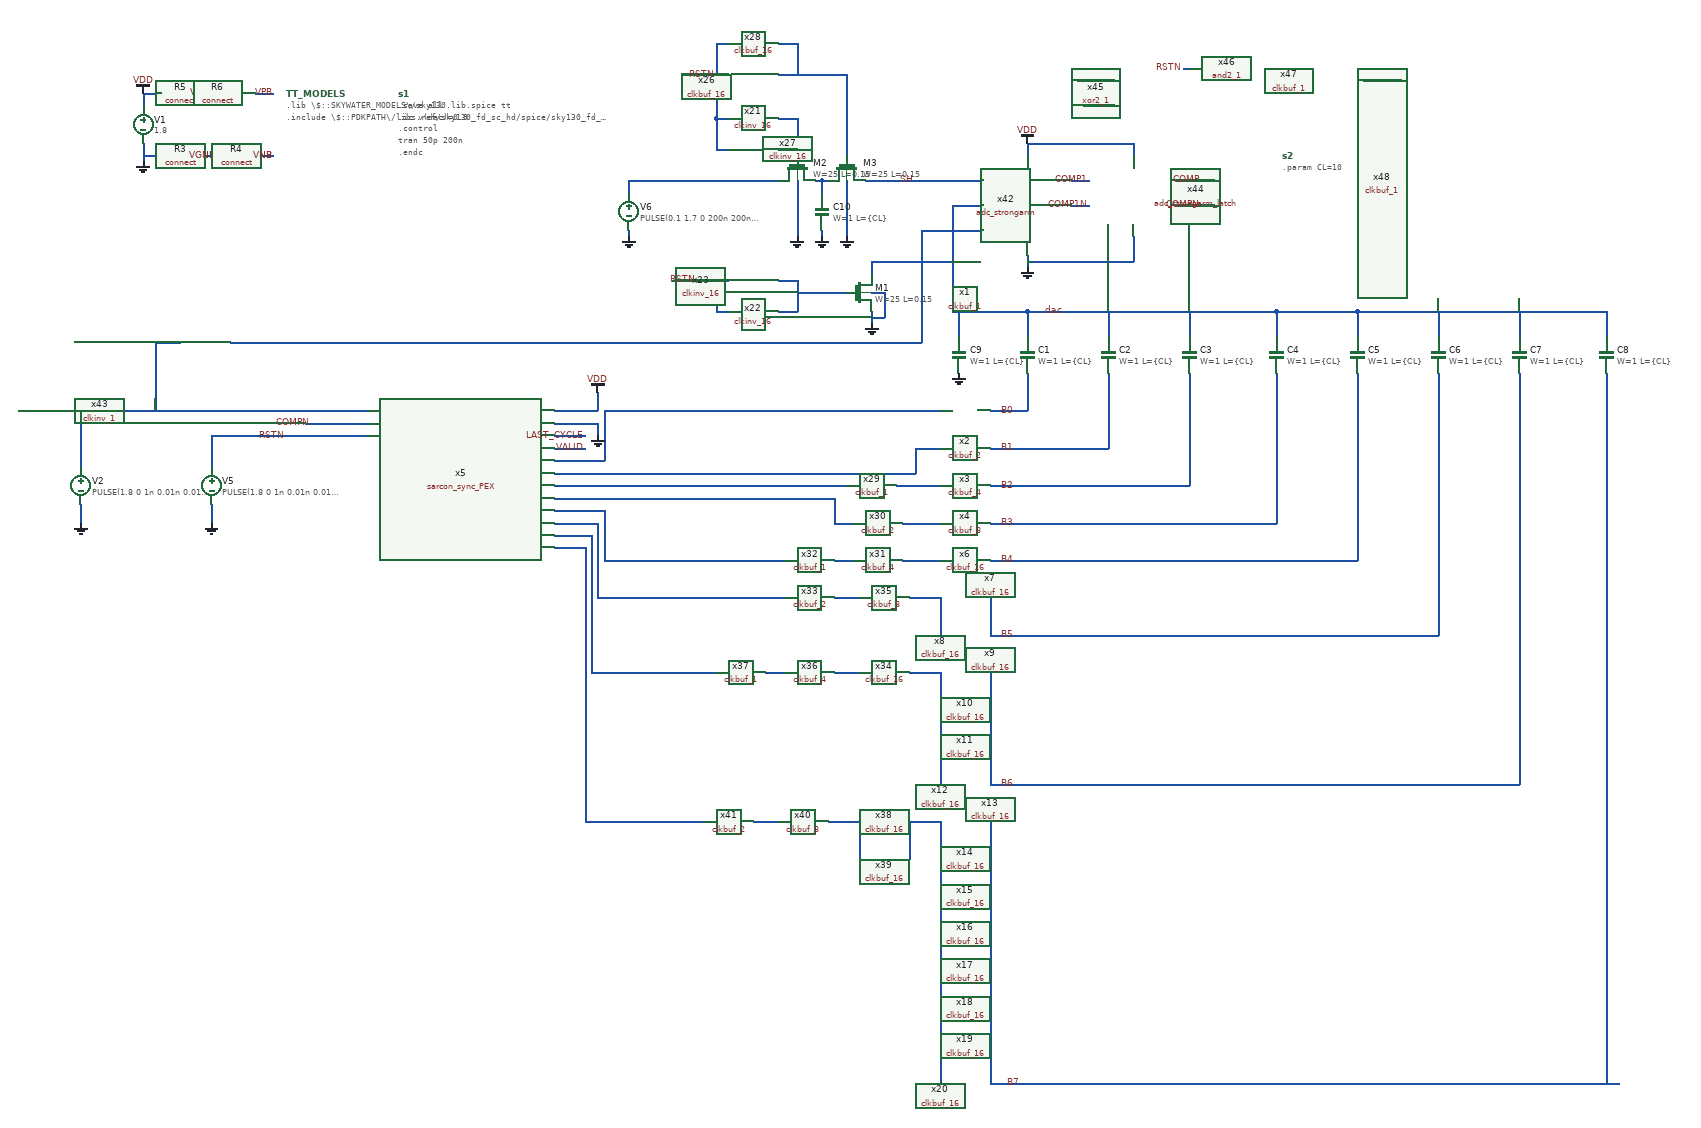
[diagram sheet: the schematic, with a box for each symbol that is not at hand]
v {xschem version=3.1.0 file_version=1.2
}
G {}
K {}
V {}
S {}
E {}
N 2640 -1240 2640 -1180 {
lab=B0}
N 2580 -1180 2640 -1180 {
lab=B0}
N 2640 -1340 2640 -1300 {
lab=dac}
N 2640 -1340 3040 -1340 {
lab=dac}
N 3040 -1340 3040 -1300 {
lab=dac}
N 2900 -1340 2900 -1300 {
lab=dac}
N 2770 -1340 2770 -1300 {
lab=dac}
N 1220 -1610 1220 -1580 {
lab=GND}
N 1220 -1590 1250 -1590 {
lab=GND}
N 1310 -1590 1340 -1590 {
lab=VGND}
N 1400 -1590 1430 -1590 {
lab=VNB}
N 1220 -1590 1250 -1590 {
lab=GND}
N 1310 -1590 1340 -1590 {
lab=VGND}
N 1400 -1590 1430 -1590 {
lab=VNB}
N 1220 -1690 1250 -1690 {
lab=VDD}
N 1310 -1690 1340 -1690 {
lab=VPWR}
N 1400 -1690 1430 -1690 {
lab=VPB}
N 1220 -1690 1220 -1670 {
lab=VDD}
N 2580 -1120 2770 -1120 {
lab=B1}
N 2770 -1240 2770 -1120 {
lab=B1}
N 2580 -1060 2900 -1060 {
lab=B2}
N 2900 -1240 2900 -1060 {
lab=B2}
N 2580 -1000 3030 -1000 {
lab=B3}
N 3030 -1000 3040 -1000 {
lab=B3}
N 3040 -1240 3040 -1000 {
lab=B3}
N 1330 -1030 1330 -1000 {
lab=GND}
N 1330 -1140 1330 -1090 {
lab=RSTN}
N 1020 -1180 1290 -1180 {
lab=#net1}
N 1880 -1180 1950 -1180 {
lab=VDD}
N 1950 -1210 1950 -1180 {
lab=VDD}
N 1880 -1160 1950 -1160 {
lab=GND}
N 1950 -1160 1950 -1140 {
lab=GND}
N 1290 -1180 1580 -1180 {
lab=#net1}
N 1540 -1140 1580 -1140 {
lab=RSTN}
N 1330 -1140 1540 -1140 {
lab=RSTN}
N 2580 -940 2640 -940 {
lab=B4}
N 3170 -1340 3570 -1340 {
lab=dac}
N 3570 -1340 3570 -1300 {
lab=dac}
N 3430 -1340 3430 -1300 {
lab=dac}
N 3300 -1340 3300 -1300 {
lab=dac}
N 3170 -1340 3170 -1300 {
lab=dac}
N 3040 -1340 3170 -1340 {
lab=dac}
N 2580 -880 2580 -820 {
lab=B5}
N 2500 -880 2500 -820 {
lab=#net2}
N 2640 -940 3170 -940 {
lab=B4}
N 3170 -1240 3170 -940 {
lab=B4}
N 2580 -820 3300 -820 {
lab=B5}
N 3300 -1240 3300 -820 {
lab=B5}
N 2500 -760 2500 -580 {
lab=#net3}
N 2580 -760 2580 -580 {
lab=B6}
N 2500 -520 2500 -340 {
lab=#net4}
N 2580 -520 2580 -340 {
lab=B7}
N 2500 -280 2500 -100 {
lab=#net4}
N 2580 -280 2580 -100 {
lab=B7}
N 2580 -340 2580 -280 {
lab=B7}
N 2500 -340 2500 -280 {
lab=#net4}
N 2580 -100 3590 -100 {
lab=B7}
N 3570 -1240 3570 -100 {
lab=B7}
N 3430 -1240 3430 -590 {
lab=B6}
N 3430 -590 3430 -580 {
lab=B6}
N 2580 -580 3430 -580 {
lab=B6}
N 1960 -1180 2010 -1180 {
lab=#net5}
N 1960 -1180 1960 -1100 {
lab=#net5}
N 1880 -1100 1960 -1100 {
lab=#net5}
N 1880 -1080 1970 -1080 {
lab=#net6}
N 2460 -1120 2460 -1080 {
lab=#net6}
N 2460 -1120 2500 -1120 {
lab=#net6}
N 1880 -1060 2010 -1060 {
lab=#net7}
N 1880 -1040 1970 -1040 {
lab=#net8}
N 2460 -1000 2500 -1000 {
lab=#net9}
N 1880 -1020 1960 -1020 {
lab=#net10}
N 1960 -1020 1960 -940 {
lab=#net10}
N 1960 -940 2010 -940 {
lab=#net10}
N 1880 -1000 1950 -1000 {
lab=#net11}
N 1950 -1000 1950 -880 {
lab=#net11}
N 1950 -880 2010 -880 {
lab=#net11}
N 1880 -980 1940 -980 {
lab=#net12}
N 1940 -980 1940 -760 {
lab=#net12}
N 1940 -760 2010 -760 {
lab=#net12}
N 1880 -960 1930 -960 {
lab=#net13}
N 1930 -960 1930 -520 {
lab=#net13}
N 1930 -520 2000 -520 {
lab=#net13}
N 2490 -520 2500 -520 {
lab=#net4}
N 2010 -1180 2500 -1180 {
lab=#net5}
N 1970 -1080 2460 -1080 {
lab=#net6}
N 2430 -1060 2500 -1060 {
lab=#net14}
N 2010 -1060 2350 -1060 {
lab=#net7}
N 2440 -1000 2460 -1000 {
lab=#net9}
N 2330 -1000 2360 -1000 {
lab=#net8}
N 2330 -1040 2330 -1000 {
lab=#net8}
N 1970 -1040 2330 -1040 {
lab=#net8}
N 2440 -940 2500 -940 {
lab=#net15}
N 2330 -940 2360 -940 {
lab=#net16}
N 2010 -940 2250 -940 {
lab=#net10}
N 2450 -880 2500 -880 {
lab=#net2}
N 2330 -880 2370 -880 {
lab=#net17}
N 2010 -880 2250 -880 {
lab=#net11}
N 2450 -760 2500 -760 {
lab=#net3}
N 2220 -760 2250 -760 {
lab=#net18}
N 2330 -760 2370 -760 {
lab=#net19}
N 2010 -760 2140 -760 {
lab=#net12}
N 2450 -520 2450 -460 {
lab=#net4}
N 2370 -520 2370 -460 {
lab=#net20}
N 2320 -520 2370 -520 {
lab=#net20}
N 2200 -520 2240 -520 {
lab=#net21}
N 2450 -520 2490 -520 {
lab=#net4}
N 2000 -520 2120 -520 {
lab=#net13}
N 2520 -1510 2570 -1510 {
lab=dac}
N 2520 -1510 2520 -1340 {
lab=dac}
N 2520 -1340 2640 -1340 {
lab=dac}
N 2470 -1470 2570 -1470 {
lab=#net22}
N 2470 -1470 2470 -1290 {
lab=#net22}
N 1360 -1290 2470 -1290 {
lab=#net22}
N 1240 -1290 1280 -1290 {
lab=#net1}
N 1240 -1290 1240 -1180 {
lab=#net1}
N 2640 -1430 2640 -1410 {
lab=GND}
N 2640 -1610 2640 -1590 {
lab=VDD}
N 2710 -1550 2740 -1550 {
lab=COMP1}
N 2710 -1510 2740 -1510 {
lab=COMP1N}
N 2640 -1420 2810 -1420 {
lab=GND}
N 2810 -1460 2810 -1420 {
lab=GND}
N 2640 -1610 2810 -1610 {
lab=VDD}
N 2810 -1610 2810 -1590 {
lab=VDD}
N 2880 -1550 2940 -1550 {
lab=COMP}
N 2880 -1510 2940 -1510 {
lab=COMPN}
N 1480 -1160 1580 -1160 {
lab=COMPN}
N 2000 -1470 2000 -1460 {
lab=GND}
N 2730 -1710 2780 -1710 {
lab=#net23}
N 2720 -1710 2730 -1710 {
lab=#net23}
N 2740 -1670 2780 -1670 {
lab=#net24}
N 2730 -1670 2740 -1670 {
lab=#net24}
N 3180 -1710 3240 -1710 {
lab=ASCLK}
N 2890 -1730 2900 -1730 {
lab=RSTN}
N 1880 -1120 1930 -1120 {
lab=VALID}
N 1880 -1140 1930 -1140 {
lab=LAST_CYCLE}
N 2530 -1340 2530 -1300 {
lab=dac}
N 2390 -1420 2390 -1400 {
lab=dac}
N 2390 -1420 2520 -1420 {
lab=dac}
N 2390 -1340 2390 -1320 {
lab=GND}
N 2390 -1330 2410 -1330 {
lab=GND}
N 2410 -1370 2410 -1330 {
lab=GND}
N 2390 -1370 2410 -1370 {
lab=GND}
N 2310 -1470 2310 -1460 {
lab=GND}
N 2000 -1550 2000 -1530 {
lab=#net25}
N 2300 -1550 2310 -1550 {
lab=#net26}
N 2310 -1550 2310 -1530 {
lab=#net26}
N 2310 -1550 2320 -1550 {
lab=#net26}
N 2350 -1550 2350 -1460 {
lab=GND}
N 2270 -1550 2270 -1460 {
lab=GND}
N 2380 -1550 2570 -1550 {
lab=SH}
N 2240 -1650 2270 -1650 {
lab=#net27}
N 2270 -1650 2270 -1590 {
lab=#net27}
N 2240 -1720 2350 -1720 {
lab=#net28}
N 2350 -1720 2350 -1590 {
lab=#net28}
N 2090 -1720 2160 -1720 {
lab=RSTN}
N 2140 -1650 2160 -1650 {
lab=RSTN}
N 2140 -1720 2140 -1650 {
lab=RSTN}
N 2240 -1600 2270 -1600 {
lab=#net27}
N 2140 -1650 2140 -1600 {
lab=RSTN}
N 2140 -1600 2160 -1600 {
lab=RSTN}
N 2240 -1770 2270 -1770 {
lab=#net28}
N 2270 -1770 2270 -1720 {
lab=#net28}
N 2140 -1770 2160 -1770 {
lab=RSTN}
N 2140 -1770 2140 -1720 {
lab=RSTN}
N 2240 -1390 2270 -1390 {
lab=#net29}
N 2270 -1390 2270 -1340 {
lab=#net29}
N 2240 -1340 2270 -1340 {
lab=#net29}
N 2270 -1370 2350 -1370 {
lab=#net29}
N 2140 -1390 2160 -1390 {
lab=RSTN}
N 2140 -1390 2140 -1340 {
lab=RSTN}
N 2140 -1340 2160 -1340 {
lab=RSTN}
N 2070 -1390 2140 -1390 {
lab=RSTN}
N 2000 -1550 2240 -1550 {
lab=#net25}
N 1120 -1180 1120 -1090 {
lab=#net1}
N 1120 -1030 1120 -1000 {
lab=GND}
C {sky130_stdcells/clkbuf_1.sym} 2540 -1180 0 0 {name=x1 VGND=VGND VNB=VNB VPB=VPB VPWR=VPWR prefix=sky130_fd_sc_hd__ }
C {sky130_fd_pr/cap_mim_m3_1.sym} 2640 -1270 0 0 {name=C1 model=cap_mim_m3_1 W=1 L=\{CL\} MF=1 spiceprefix=X}
C {devices/lab_wire.sym} 2700 -1340 0 0 {name=p1 sig_type=std_logic lab=dac}
C {devices/vsource.sym} 1220 -1640 0 0 {name=V1 value=1.8}
C {devices/gnd.sym} 1220 -1580 0 0 {name=l1 lab=GND}
C {devices/lab_wire.sym} 1340 -1590 0 0 {name=p2 sig_type=std_logic lab=VGND}
C {devices/lab_wire.sym} 1430 -1590 0 0 {name=p3 sig_type=std_logic lab=VNB}
C {devices/connect.sym} 1280 -1590 1 0 {name=R3 m=1}
C {devices/lab_wire.sym} 1340 -1590 0 0 {name=p4 sig_type=std_logic lab=VGND}
C {devices/connect.sym} 1370 -1590 1 0 {name=R4 m=1}
C {devices/lab_wire.sym} 1430 -1590 0 0 {name=p5 sig_type=std_logic lab=VNB}
C {devices/connect.sym} 1280 -1690 1 0 {name=R5 m=1}
C {devices/lab_wire.sym} 1340 -1690 0 0 {name=p6 sig_type=std_logic lab=VPWR}
C {devices/connect.sym} 1370 -1690 1 0 {name=R6 m=1}
C {devices/lab_wire.sym} 1430 -1690 0 0 {name=p7 sig_type=std_logic lab=VPB}
C {devices/vsource.sym} 1330 -1060 0 0 {name=V5 value="PULSE(1.8 0 1n 0.01n 0.01n 4n 20n)"}
C {devices/gnd.sym} 1330 -1000 0 0 {name=l2 lab=GND}
C {devices/code.sym} 1450 -1690 0 0 {name=TT_MODELS only_toplevel=false
format="tcleval(@value )" value=".lib \\\\$::SKYWATER_MODELS\\\\/sky130.lib.spice tt
.include \\\\$::PDKPATH\\\\/libs.ref/sky130_fd_sc_hd/spice/sky130_fd_sc_hd.spice
"}
C {devices/code_shown.sym} 1630 -1690 0 0 {name=s1
only_toplevel=false
value="
.save all
.ic v(dac)=0.9
.control
tran 50p 200n
.endc
"}
C {devices/lab_wire.sym} 2620 -1180 0 0 {name=p8 sig_type=std_logic lab=B0}
C {devices/lab_wire.sym} 2620 -1120 0 0 {name=p9 sig_type=std_logic lab=B1}
C {devices/lab_wire.sym} 2620 -1060 0 0 {name=p10 sig_type=std_logic lab=B2}
C {devices/lab_wire.sym} 2620 -1000 0 0 {name=p11 sig_type=std_logic lab=B3}
C {sky130_stdcells/clkbuf_2.sym} 2540 -1120 0 0 {name=x2 VGND=VGND VNB=VNB VPB=VPB VPWR=VPWR prefix=sky130_fd_sc_hd__ }
C {sky130_stdcells/clkbuf_4.sym} 2540 -1060 0 0 {name=x3 VGND=VGND VNB=VNB VPB=VPB VPWR=VPWR prefix=sky130_fd_sc_hd__ }
C {sky130_stdcells/clkbuf_8.sym} 2540 -1000 0 0 {name=x4 VGND=VGND VNB=VNB VPB=VPB VPWR=VPWR prefix=sky130_fd_sc_hd__ }
C {sarcon_sync_PEX.sym} 1730 -1070 0 0 {name=x5}
C {devices/gnd.sym} 1950 -1140 0 0 {name=l3 lab=GND}
C {devices/vdd.sym} 1220 -1690 0 0 {name=l4 lab=VDD}
C {devices/vdd.sym} 1950 -1210 0 0 {name=l5 lab=VDD}
C {sky130_fd_pr/cap_mim_m3_1.sym} 2770 -1270 0 0 {name=C2 model=cap_mim_m3_1 W=1 L=\{CL\} MF=2 spiceprefix=X}
C {sky130_fd_pr/cap_mim_m3_1.sym} 2900 -1270 0 0 {name=C3 model=cap_mim_m3_1 W=1 L=\{CL\} MF=4 spiceprefix=X}
C {sky130_fd_pr/cap_mim_m3_1.sym} 3040 -1270 0 0 {name=C4 model=cap_mim_m3_1 W=1 L=\{CL\} MF=8 spiceprefix=X}
C {sky130_fd_pr/cap_mim_m3_1.sym} 3170 -1270 0 0 {name=C5 model=cap_mim_m3_1 W=1 L=\{CL\} MF=16 spiceprefix=X}
C {sky130_fd_pr/cap_mim_m3_1.sym} 3300 -1270 0 0 {name=C6 model=cap_mim_m3_1 W=1 L=\{CL\} MF=32 spiceprefix=X}
C {sky130_fd_pr/cap_mim_m3_1.sym} 3430 -1270 0 0 {name=C7 model=cap_mim_m3_1 W=1 L=\{CL\} MF=64 spiceprefix=X}
C {sky130_fd_pr/cap_mim_m3_1.sym} 3570 -1270 0 0 {name=C8 model=cap_mim_m3_1 W=1 L=\{CL\} MF=128 spiceprefix=X}
C {sky130_stdcells/clkbuf_16.sym} 2540 -940 0 0 {name=x6 VGND=VGND VNB=VNB VPB=VPB VPWR=VPWR prefix=sky130_fd_sc_hd__ }
C {devices/lab_wire.sym} 2620 -940 0 0 {name=p12 sig_type=std_logic lab=B4}
C {devices/lab_wire.sym} 2620 -820 0 0 {name=p13 sig_type=std_logic lab=B5}
C {devices/lab_wire.sym} 2620 -580 0 0 {name=p14 sig_type=std_logic lab=B6}
C {devices/lab_wire.sym} 2630 -100 0 0 {name=p15 sig_type=std_logic lab=B7}
C {sky130_stdcells/clkbuf_16.sym} 2540 -880 0 0 {name=x7 VGND=VGND VNB=VNB VPB=VPB VPWR=VPWR prefix=sky130_fd_sc_hd__ }
C {sky130_stdcells/clkbuf_16.sym} 2540 -820 0 0 {name=x8 VGND=VGND VNB=VNB VPB=VPB VPWR=VPWR prefix=sky130_fd_sc_hd__ }
C {sky130_stdcells/clkbuf_16.sym} 2540 -760 0 0 {name=x9 VGND=VGND VNB=VNB VPB=VPB VPWR=VPWR prefix=sky130_fd_sc_hd__ }
C {sky130_stdcells/clkbuf_16.sym} 2540 -700 0 0 {name=x10 VGND=VGND VNB=VNB VPB=VPB VPWR=VPWR prefix=sky130_fd_sc_hd__ }
C {sky130_stdcells/clkbuf_16.sym} 2540 -640 0 0 {name=x11 VGND=VGND VNB=VNB VPB=VPB VPWR=VPWR prefix=sky130_fd_sc_hd__ }
C {sky130_stdcells/clkbuf_16.sym} 2540 -580 0 0 {name=x12 VGND=VGND VNB=VNB VPB=VPB VPWR=VPWR prefix=sky130_fd_sc_hd__ }
C {sky130_stdcells/clkbuf_16.sym} 2540 -520 0 0 {name=x13 VGND=VGND VNB=VNB VPB=VPB VPWR=VPWR prefix=sky130_fd_sc_hd__ }
C {sky130_stdcells/clkbuf_16.sym} 2540 -460 0 0 {name=x14 VGND=VGND VNB=VNB VPB=VPB VPWR=VPWR prefix=sky130_fd_sc_hd__ }
C {sky130_stdcells/clkbuf_16.sym} 2540 -400 0 0 {name=x15 VGND=VGND VNB=VNB VPB=VPB VPWR=VPWR prefix=sky130_fd_sc_hd__ }
C {sky130_stdcells/clkbuf_16.sym} 2540 -340 0 0 {name=x16 VGND=VGND VNB=VNB VPB=VPB VPWR=VPWR prefix=sky130_fd_sc_hd__ }
C {sky130_stdcells/clkbuf_16.sym} 2540 -280 0 0 {name=x17 VGND=VGND VNB=VNB VPB=VPB VPWR=VPWR prefix=sky130_fd_sc_hd__ }
C {sky130_stdcells/clkbuf_16.sym} 2540 -220 0 0 {name=x18 VGND=VGND VNB=VNB VPB=VPB VPWR=VPWR prefix=sky130_fd_sc_hd__ }
C {sky130_stdcells/clkbuf_16.sym} 2540 -160 0 0 {name=x19 VGND=VGND VNB=VNB VPB=VPB VPWR=VPWR prefix=sky130_fd_sc_hd__ }
C {sky130_stdcells/clkbuf_16.sym} 2540 -100 0 0 {name=x20 VGND=VGND VNB=VNB VPB=VPB VPWR=VPWR prefix=sky130_fd_sc_hd__ }
C {sky130_fd_pr/nfet_01v8.sym} 2370 -1370 0 0 {name=M1
L=0.15
W=25
nf=1 
mult=8
ad="'int((nf+1)/2) * W/nf * 0.29'" 
pd="'2*int((nf+1)/2) * (W/nf + 0.29)'"
as="'int((nf+2)/2) * W/nf * 0.29'" 
ps="'2*int((nf+2)/2) * (W/nf + 0.29)'"
nrd="'0.29 / W'" nrs="'0.29 / W'"
sa=0 sb=0 sd=0
model=nfet_01v8
spiceprefix=X
}
C {sky130_stdcells/clkinv_16.sym} 2200 -1340 0 0 {name=x22 VGND=VGND VNB=VNB VPB=VPB VPWR=VPWR prefix=sky130_fd_sc_hd__ }
C {sky130_stdcells/clkinv_16.sym} 2200 -1390 0 0 {name=x23 VGND=VGND VNB=VNB VPB=VPB VPWR=VPWR prefix=sky130_fd_sc_hd__ }
C {sky130_stdcells/clkbuf_1.sym} 2390 -1060 0 0 {name=x29 VGND=VGND VNB=VNB VPB=VPB VPWR=VPWR prefix=sky130_fd_sc_hd__ }
C {sky130_stdcells/clkbuf_2.sym} 2400 -1000 0 0 {name=x30 VGND=VGND VNB=VNB VPB=VPB VPWR=VPWR prefix=sky130_fd_sc_hd__ }
C {sky130_stdcells/clkbuf_4.sym} 2400 -940 0 0 {name=x31 VGND=VGND VNB=VNB VPB=VPB VPWR=VPWR prefix=sky130_fd_sc_hd__ }
C {sky130_stdcells/clkbuf_1.sym} 2290 -940 0 0 {name=x32 VGND=VGND VNB=VNB VPB=VPB VPWR=VPWR prefix=sky130_fd_sc_hd__ }
C {sky130_stdcells/clkbuf_8.sym} 2410 -880 0 0 {name=x35 VGND=VGND VNB=VNB VPB=VPB VPWR=VPWR prefix=sky130_fd_sc_hd__ }
C {sky130_stdcells/clkbuf_2.sym} 2290 -880 0 0 {name=x33 VGND=VGND VNB=VNB VPB=VPB VPWR=VPWR prefix=sky130_fd_sc_hd__ }
C {sky130_stdcells/clkbuf_16.sym} 2410 -760 0 0 {name=x34 VGND=VGND VNB=VNB VPB=VPB VPWR=VPWR prefix=sky130_fd_sc_hd__ }
C {sky130_stdcells/clkbuf_4.sym} 2290 -760 0 0 {name=x36 VGND=VGND VNB=VNB VPB=VPB VPWR=VPWR prefix=sky130_fd_sc_hd__ }
C {sky130_stdcells/clkbuf_1.sym} 2180 -760 0 0 {name=x37 VGND=VGND VNB=VNB VPB=VPB VPWR=VPWR prefix=sky130_fd_sc_hd__ }
C {sky130_stdcells/clkbuf_16.sym} 2410 -520 0 0 {name=x38 VGND=VGND VNB=VNB VPB=VPB VPWR=VPWR prefix=sky130_fd_sc_hd__ }
C {sky130_stdcells/clkbuf_16.sym} 2410 -460 0 0 {name=x39 VGND=VGND VNB=VNB VPB=VPB VPWR=VPWR prefix=sky130_fd_sc_hd__ }
C {sky130_stdcells/clkbuf_8.sym} 2280 -520 0 0 {name=x40 VGND=VGND VNB=VNB VPB=VPB VPWR=VPWR prefix=sky130_fd_sc_hd__ }
C {sky130_stdcells/clkbuf_2.sym} 2160 -520 0 0 {name=x41 VGND=VGND VNB=VNB VPB=VPB VPWR=VPWR prefix=sky130_fd_sc_hd__ }
C {adc_strongarm.sym} 2640 -1510 0 0 {name=x42}
C {sky130_stdcells/clkinv_1.sym} 1320 -1290 0 0 {name=x43 VGND=VGND VNB=VNB VPB=VPB VPWR=VPWR prefix=sky130_fd_sc_hd__ }
C {devices/gnd.sym} 2640 -1410 0 0 {name=l9 lab=GND}
C {devices/vdd.sym} 2640 -1610 0 0 {name=l10 lab=VDD}
C {adc_strongarm_latch.sym} 2810 -1520 0 0 {name=x44}
C {devices/lab_wire.sym} 2920 -1550 0 0 {name=p16 sig_type=std_logic lab=COMP}
C {devices/lab_wire.sym} 2920 -1510 0 0 {name=p17 sig_type=std_logic lab=COMPN}
C {devices/lab_wire.sym} 1490 -1160 0 0 {name=p18 sig_type=std_logic lab=COMPN}
C {devices/lab_wire.sym} 1450 -1140 0 0 {name=p20 sig_type=std_logic lab=RSTN}
C {devices/vsource.sym} 2000 -1500 0 1 {name=V6 value="PULSE(0.1 1.7 0 200n 200n 0 400n )"}
C {devices/gnd.sym} 2000 -1460 0 0 {name=l11 lab=GND}
C {sky130_stdcells/xor2_1.sym} 2840 -1690 0 0 {name=x45 VGND=VGND VNB=VNB VPB=VPB VPWR=VPWR prefix=sky130_fd_sc_hd__ }
C {devices/lab_wire.sym} 3230 -1710 0 0 {name=p21 sig_type=std_logic lab=ASCLK}
C {sky130_stdcells/and2_1.sym} 2960 -1710 0 0 {name=x46 VGND=VGND VNB=VNB VPB=VPB VPWR=VPWR prefix=sky130_fd_sc_hd__ }
C {devices/lab_wire.sym} 2890 -1730 0 0 {name=p19 sig_type=std_logic lab=RSTN}
C {devices/code_shown.sym} 3050 -1590 0 0 {name=s2 only_toplevel=false value=".param CL=10
"}
C {devices/lab_wire.sym} 1930 -1140 0 0 {name=p23 sig_type=std_logic lab=LAST_CYCLE}
C {devices/lab_wire.sym} 1930 -1120 0 0 {name=p24 sig_type=std_logic lab=VALID}
C {sky130_fd_pr/cap_mim_m3_1.sym} 2530 -1270 0 0 {name=C9 model=cap_mim_m3_1 W=1 L=\{CL\} MF=1 spiceprefix=X}
C {devices/gnd.sym} 2530 -1240 0 0 {name=l12 lab=GND}
C {sky130_stdcells/clkbuf_1.sym} 3060 -1710 0 0 {name=x47 VGND=VGND VNB=VNB VPB=VPB VPWR=VPWR prefix=sky130_fd_sc_hd__ }
C {sky130_stdcells/clkbuf_1.sym} 3140 -1710 0 0 {name=x48 VGND=VGND VNB=VNB VPB=VPB VPWR=VPWR prefix=sky130_fd_sc_hd__ }
C {sky130_fd_pr/cap_mim_m3_1.sym} 2310 -1500 0 0 {name=C10 model=cap_mim_m3_1 W=1 L=\{CL\} MF=8 spiceprefix=X}
C {devices/gnd.sym} 2310 -1460 0 0 {name=l7 lab=GND}
C {sky130_fd_pr/nfet_01v8.sym} 2270 -1570 1 0 {name=M2
L=0.15
W=25
nf=1 
mult=8
ad="'int((nf+1)/2) * W/nf * 0.29'" 
pd="'2*int((nf+1)/2) * (W/nf + 0.29)'"
as="'int((nf+2)/2) * W/nf * 0.29'" 
ps="'2*int((nf+2)/2) * (W/nf + 0.29)'"
nrd="'0.29 / W'" nrs="'0.29 / W'"
sa=0 sb=0 sd=0
model=nfet_01v8
spiceprefix=X
}
C {sky130_fd_pr/nfet_01v8.sym} 2350 -1570 1 0 {name=M3
L=0.15
W=25
nf=1 
mult=8
ad="'int((nf+1)/2) * W/nf * 0.29'" 
pd="'2*int((nf+1)/2) * (W/nf + 0.29)'"
as="'int((nf+2)/2) * W/nf * 0.29'" 
ps="'2*int((nf+2)/2) * (W/nf + 0.29)'"
nrd="'0.29 / W'" nrs="'0.29 / W'"
sa=0 sb=0 sd=0
model=nfet_01v8
spiceprefix=X
}
C {devices/gnd.sym} 2350 -1460 0 0 {name=l8 lab=GND}
C {devices/gnd.sym} 2270 -1460 0 0 {name=l13 lab=GND}
C {sky130_stdcells/clkinv_16.sym} 2200 -1650 0 0 {name=x21 VGND=VGND VNB=VNB VPB=VPB VPWR=VPWR prefix=sky130_fd_sc_hd__ }
C {sky130_stdcells/clkbuf_16.sym} 2200 -1720 0 0 {name=x26 VGND=VGND VNB=VNB VPB=VPB VPWR=VPWR prefix=sky130_fd_sc_hd__ }
C {devices/lab_wire.sym} 2140 -1720 0 0 {name=p25 sig_type=std_logic lab=RSTN}
C {devices/lab_wire.sym} 2460 -1550 0 0 {name=p26 sig_type=std_logic lab=SH}
C {sky130_stdcells/clkinv_16.sym} 2200 -1600 0 0 {name=x27 VGND=VGND VNB=VNB VPB=VPB VPWR=VPWR prefix=sky130_fd_sc_hd__ }
C {sky130_stdcells/clkbuf_16.sym} 2200 -1770 0 0 {name=x28 VGND=VGND VNB=VNB VPB=VPB VPWR=VPWR prefix=sky130_fd_sc_hd__ }
C {devices/lab_wire.sym} 2110 -1390 0 0 {name=p27 sig_type=std_logic lab=RSTN}
C {devices/vsource.sym} 1120 -1060 0 0 {name=V2 value="PULSE(1.8 0 1n 0.01n 0.01n 1n 2n)"}
C {devices/gnd.sym} 1120 -1000 0 0 {name=l14 lab=GND}
C {devices/gnd.sym} 2390 -1320 0 0 {name=l6 lab=GND}
C {devices/lab_wire.sym} 2740 -1550 0 0 {name=p22 sig_type=std_logic lab=COMP1}
C {devices/lab_wire.sym} 2740 -1510 0 0 {name=p28 sig_type=std_logic lab=COMP1N}
